# Generated by OpenFakeRAM
VERSION 5.7 ;
BUSBITCHARS "[]" ;
PROPERTYDEFINITIONS
  MACRO width INTEGER ;
  MACRO depth INTEGER ;
  MACRO banks INTEGER ;
END PROPERTYDEFINITIONS
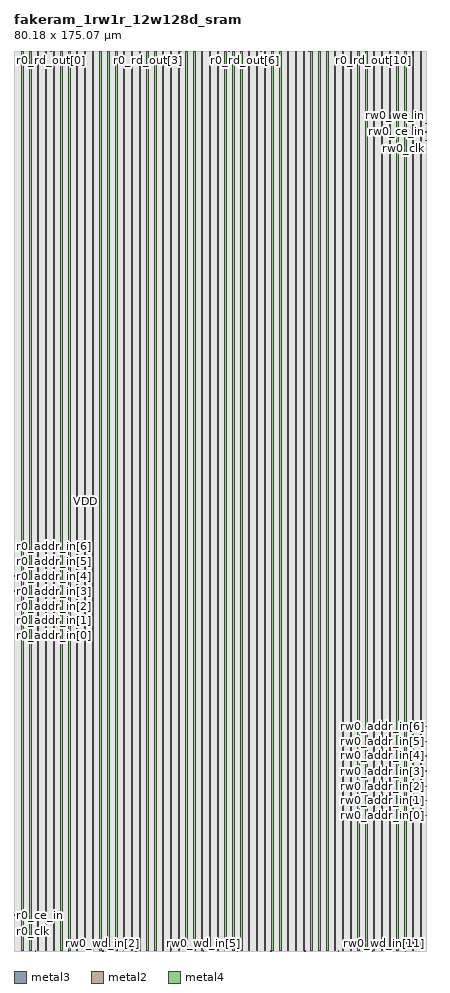
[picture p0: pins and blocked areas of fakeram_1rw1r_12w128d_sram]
MACRO fakeram_1rw1r_12w128d_sram
  PROPERTY width 12 ;
  PROPERTY depth 128 ;
  PROPERTY banks 1 ;
  FOREIGN fakeram_1rw1r_12w128d_sram 0 0 ;
  SYMMETRY X Y R90 ;
  SIZE 80.180 BY 175.070 ;
  CLASS BLOCK ;
  PIN r0_clk
    DIRECTION INPUT ;
    USE SIGNAL ;
    SHAPE ABUTMENT ;
    PORT
      LAYER metal3 ;
      RECT 0.000 5.285 0.070 5.355 ;
    END
  END r0_clk
  PIN r0_ce_in
    DIRECTION INPUT ;
    USE SIGNAL ;
    SHAPE ABUTMENT ;
    PORT
      LAYER metal3 ;
      RECT 0.000 6.965 0.070 7.035 ;
    END
  END r0_ce_in
  PIN r0_addr_in[0]
    DIRECTION INPUT ;
    USE SIGNAL ;
    SHAPE ABUTMENT ;
    PORT
      LAYER metal3 ;
      RECT 0.000 61.285 0.070 61.355 ;
    END
  END r0_addr_in[0]
  PIN r0_addr_in[1]
    DIRECTION INPUT ;
    USE SIGNAL ;
    SHAPE ABUTMENT ;
    PORT
      LAYER metal3 ;
      RECT 0.000 64.225 0.070 64.295 ;
    END
  END r0_addr_in[1]
  PIN r0_addr_in[2]
    DIRECTION INPUT ;
    USE SIGNAL ;
    SHAPE ABUTMENT ;
    PORT
      LAYER metal3 ;
      RECT 0.000 67.025 0.070 67.095 ;
    END
  END r0_addr_in[2]
  PIN r0_addr_in[3]
    DIRECTION INPUT ;
    USE SIGNAL ;
    SHAPE ABUTMENT ;
    PORT
      LAYER metal3 ;
      RECT 0.000 69.965 0.070 70.035 ;
    END
  END r0_addr_in[3]
  PIN r0_addr_in[4]
    DIRECTION INPUT ;
    USE SIGNAL ;
    SHAPE ABUTMENT ;
    PORT
      LAYER metal3 ;
      RECT 0.000 72.905 0.070 72.975 ;
    END
  END r0_addr_in[4]
  PIN r0_addr_in[5]
    DIRECTION INPUT ;
    USE SIGNAL ;
    SHAPE ABUTMENT ;
    PORT
      LAYER metal3 ;
      RECT 0.000 75.705 0.070 75.775 ;
    END
  END r0_addr_in[5]
  PIN r0_addr_in[6]
    DIRECTION INPUT ;
    USE SIGNAL ;
    SHAPE ABUTMENT ;
    PORT
      LAYER metal3 ;
      RECT 0.000 78.645 0.070 78.715 ;
    END
  END r0_addr_in[6]
  PIN rw0_rd_out[0]
    DIRECTION OUTPUT ;
    USE SIGNAL ;
    SHAPE ABUTMENT ;
    PORT
      LAYER metal2 ;
      RECT 4.145 175.000 4.215 175.070 ;
    END
  END rw0_rd_out[0]
  PIN r0_rd_out[0]
    DIRECTION OUTPUT ;
    USE SIGNAL ;
    SHAPE ABUTMENT ;
    PORT
      LAYER metal2 ;
      RECT 7.185 175.000 7.255 175.070 ;
    END
  END r0_rd_out[0]
  PIN rw0_rd_out[1]
    DIRECTION OUTPUT ;
    USE SIGNAL ;
    SHAPE ABUTMENT ;
    PORT
      LAYER metal2 ;
      RECT 10.415 175.000 10.485 175.070 ;
    END
  END rw0_rd_out[1]
  PIN r0_rd_out[1]
    DIRECTION OUTPUT ;
    USE SIGNAL ;
    SHAPE ABUTMENT ;
    PORT
      LAYER metal2 ;
      RECT 13.455 175.000 13.525 175.070 ;
    END
  END r0_rd_out[1]
  PIN rw0_rd_out[2]
    DIRECTION OUTPUT ;
    USE SIGNAL ;
    SHAPE ABUTMENT ;
    PORT
      LAYER metal2 ;
      RECT 16.685 175.000 16.755 175.070 ;
    END
  END rw0_rd_out[2]
  PIN r0_rd_out[2]
    DIRECTION OUTPUT ;
    USE SIGNAL ;
    SHAPE ABUTMENT ;
    PORT
      LAYER metal2 ;
      RECT 19.725 175.000 19.795 175.070 ;
    END
  END r0_rd_out[2]
  PIN rw0_rd_out[3]
    DIRECTION OUTPUT ;
    USE SIGNAL ;
    SHAPE ABUTMENT ;
    PORT
      LAYER metal2 ;
      RECT 22.955 175.000 23.025 175.070 ;
    END
  END rw0_rd_out[3]
  PIN r0_rd_out[3]
    DIRECTION OUTPUT ;
    USE SIGNAL ;
    SHAPE ABUTMENT ;
    PORT
      LAYER metal2 ;
      RECT 25.995 175.000 26.065 175.070 ;
    END
  END r0_rd_out[3]
  PIN rw0_rd_out[4]
    DIRECTION OUTPUT ;
    USE SIGNAL ;
    SHAPE ABUTMENT ;
    PORT
      LAYER metal2 ;
      RECT 29.225 175.000 29.295 175.070 ;
    END
  END rw0_rd_out[4]
  PIN r0_rd_out[4]
    DIRECTION OUTPUT ;
    USE SIGNAL ;
    SHAPE ABUTMENT ;
    PORT
      LAYER metal2 ;
      RECT 32.265 175.000 32.335 175.070 ;
    END
  END r0_rd_out[4]
  PIN rw0_rd_out[5]
    DIRECTION OUTPUT ;
    USE SIGNAL ;
    SHAPE ABUTMENT ;
    PORT
      LAYER metal2 ;
      RECT 35.495 175.000 35.565 175.070 ;
    END
  END rw0_rd_out[5]
  PIN r0_rd_out[5]
    DIRECTION OUTPUT ;
    USE SIGNAL ;
    SHAPE ABUTMENT ;
    PORT
      LAYER metal2 ;
      RECT 38.535 175.000 38.605 175.070 ;
    END
  END r0_rd_out[5]
  PIN rw0_rd_out[6]
    DIRECTION OUTPUT ;
    USE SIGNAL ;
    SHAPE ABUTMENT ;
    PORT
      LAYER metal2 ;
      RECT 41.765 175.000 41.835 175.070 ;
    END
  END rw0_rd_out[6]
  PIN r0_rd_out[6]
    DIRECTION OUTPUT ;
    USE SIGNAL ;
    SHAPE ABUTMENT ;
    PORT
      LAYER metal2 ;
      RECT 44.805 175.000 44.875 175.070 ;
    END
  END r0_rd_out[6]
  PIN rw0_rd_out[7]
    DIRECTION OUTPUT ;
    USE SIGNAL ;
    SHAPE ABUTMENT ;
    PORT
      LAYER metal2 ;
      RECT 48.035 175.000 48.105 175.070 ;
    END
  END rw0_rd_out[7]
  PIN r0_rd_out[7]
    DIRECTION OUTPUT ;
    USE SIGNAL ;
    SHAPE ABUTMENT ;
    PORT
      LAYER metal2 ;
      RECT 51.075 175.000 51.145 175.070 ;
    END
  END r0_rd_out[7]
  PIN rw0_rd_out[8]
    DIRECTION OUTPUT ;
    USE SIGNAL ;
    SHAPE ABUTMENT ;
    PORT
      LAYER metal2 ;
      RECT 54.305 175.000 54.375 175.070 ;
    END
  END rw0_rd_out[8]
  PIN r0_rd_out[8]
    DIRECTION OUTPUT ;
    USE SIGNAL ;
    SHAPE ABUTMENT ;
    PORT
      LAYER metal2 ;
      RECT 57.345 175.000 57.415 175.070 ;
    END
  END r0_rd_out[8]
  PIN rw0_rd_out[9]
    DIRECTION OUTPUT ;
    USE SIGNAL ;
    SHAPE ABUTMENT ;
    PORT
      LAYER metal2 ;
      RECT 60.575 175.000 60.645 175.070 ;
    END
  END rw0_rd_out[9]
  PIN r0_rd_out[9]
    DIRECTION OUTPUT ;
    USE SIGNAL ;
    SHAPE ABUTMENT ;
    PORT
      LAYER metal2 ;
      RECT 63.615 175.000 63.685 175.070 ;
    END
  END r0_rd_out[9]
  PIN rw0_rd_out[10]
    DIRECTION OUTPUT ;
    USE SIGNAL ;
    SHAPE ABUTMENT ;
    PORT
      LAYER metal2 ;
      RECT 66.845 175.000 66.915 175.070 ;
    END
  END rw0_rd_out[10]
  PIN r0_rd_out[10]
    DIRECTION OUTPUT ;
    USE SIGNAL ;
    SHAPE ABUTMENT ;
    PORT
      LAYER metal2 ;
      RECT 69.885 175.000 69.955 175.070 ;
    END
  END r0_rd_out[10]
  PIN rw0_rd_out[11]
    DIRECTION OUTPUT ;
    USE SIGNAL ;
    SHAPE ABUTMENT ;
    PORT
      LAYER metal2 ;
      RECT 73.115 175.000 73.185 175.070 ;
    END
  END rw0_rd_out[11]
  PIN r0_rd_out[11]
    DIRECTION OUTPUT ;
    USE SIGNAL ;
    SHAPE ABUTMENT ;
    PORT
      LAYER metal2 ;
      RECT 76.155 175.000 76.225 175.070 ;
    END
  END r0_rd_out[11]
  PIN rw0_clk
    DIRECTION INPUT ;
    USE SIGNAL ;
    SHAPE ABUTMENT ;
    PORT
      LAYER metal3 ;
      RECT 80.110 157.605 80.180 157.675 ;
    END
  END rw0_clk
  PIN rw0_ce_in
    DIRECTION INPUT ;
    USE SIGNAL ;
    SHAPE ABUTMENT ;
    PORT
      LAYER metal3 ;
      RECT 80.110 159.285 80.180 159.355 ;
    END
  END rw0_ce_in
  PIN rw0_we_in
    DIRECTION INPUT ;
    USE SIGNAL ;
    SHAPE ABUTMENT ;
    PORT
      LAYER metal3 ;
      RECT 80.110 160.965 80.180 161.035 ;
    END
  END rw0_we_in
  PIN rw0_addr_in[0]
    DIRECTION INPUT ;
    USE SIGNAL ;
    SHAPE ABUTMENT ;
    PORT
      LAYER metal3 ;
      RECT 80.110 26.285 80.180 26.355 ;
    END
  END rw0_addr_in[0]
  PIN rw0_addr_in[1]
    DIRECTION INPUT ;
    USE SIGNAL ;
    SHAPE ABUTMENT ;
    PORT
      LAYER metal3 ;
      RECT 80.110 29.225 80.180 29.295 ;
    END
  END rw0_addr_in[1]
  PIN rw0_addr_in[2]
    DIRECTION INPUT ;
    USE SIGNAL ;
    SHAPE ABUTMENT ;
    PORT
      LAYER metal3 ;
      RECT 80.110 32.025 80.180 32.095 ;
    END
  END rw0_addr_in[2]
  PIN rw0_addr_in[3]
    DIRECTION INPUT ;
    USE SIGNAL ;
    SHAPE ABUTMENT ;
    PORT
      LAYER metal3 ;
      RECT 80.110 34.965 80.180 35.035 ;
    END
  END rw0_addr_in[3]
  PIN rw0_addr_in[4]
    DIRECTION INPUT ;
    USE SIGNAL ;
    SHAPE ABUTMENT ;
    PORT
      LAYER metal3 ;
      RECT 80.110 37.905 80.180 37.975 ;
    END
  END rw0_addr_in[4]
  PIN rw0_addr_in[5]
    DIRECTION INPUT ;
    USE SIGNAL ;
    SHAPE ABUTMENT ;
    PORT
      LAYER metal3 ;
      RECT 80.110 40.705 80.180 40.775 ;
    END
  END rw0_addr_in[5]
  PIN rw0_addr_in[6]
    DIRECTION INPUT ;
    USE SIGNAL ;
    SHAPE ABUTMENT ;
    PORT
      LAYER metal3 ;
      RECT 80.110 43.645 80.180 43.715 ;
    END
  END rw0_addr_in[6]
  PIN rw0_wd_in[0]
    DIRECTION INPUT ;
    USE SIGNAL ;
    SHAPE ABUTMENT ;
    PORT
      LAYER metal2 ;
      RECT 4.145 0.000 4.215 0.070 ;
    END
  END rw0_wd_in[0]
  PIN rw0_wd_in[1]
    DIRECTION INPUT ;
    USE SIGNAL ;
    SHAPE ABUTMENT ;
    PORT
      LAYER metal2 ;
      RECT 10.605 0.000 10.675 0.070 ;
    END
  END rw0_wd_in[1]
  PIN rw0_wd_in[2]
    DIRECTION INPUT ;
    USE SIGNAL ;
    SHAPE ABUTMENT ;
    PORT
      LAYER metal2 ;
      RECT 17.255 0.000 17.325 0.070 ;
    END
  END rw0_wd_in[2]
  PIN rw0_wd_in[3]
    DIRECTION INPUT ;
    USE SIGNAL ;
    SHAPE ABUTMENT ;
    PORT
      LAYER metal2 ;
      RECT 23.715 0.000 23.785 0.070 ;
    END
  END rw0_wd_in[3]
  PIN rw0_wd_in[4]
    DIRECTION INPUT ;
    USE SIGNAL ;
    SHAPE ABUTMENT ;
    PORT
      LAYER metal2 ;
      RECT 30.365 0.000 30.435 0.070 ;
    END
  END rw0_wd_in[4]
  PIN rw0_wd_in[5]
    DIRECTION INPUT ;
    USE SIGNAL ;
    SHAPE ABUTMENT ;
    PORT
      LAYER metal2 ;
      RECT 36.825 0.000 36.895 0.070 ;
    END
  END rw0_wd_in[5]
  PIN rw0_wd_in[6]
    DIRECTION INPUT ;
    USE SIGNAL ;
    SHAPE ABUTMENT ;
    PORT
      LAYER metal2 ;
      RECT 43.475 0.000 43.545 0.070 ;
    END
  END rw0_wd_in[6]
  PIN rw0_wd_in[7]
    DIRECTION INPUT ;
    USE SIGNAL ;
    SHAPE ABUTMENT ;
    PORT
      LAYER metal2 ;
      RECT 49.935 0.000 50.005 0.070 ;
    END
  END rw0_wd_in[7]
  PIN rw0_wd_in[8]
    DIRECTION INPUT ;
    USE SIGNAL ;
    SHAPE ABUTMENT ;
    PORT
      LAYER metal2 ;
      RECT 56.585 0.000 56.655 0.070 ;
    END
  END rw0_wd_in[8]
  PIN rw0_wd_in[9]
    DIRECTION INPUT ;
    USE SIGNAL ;
    SHAPE ABUTMENT ;
    PORT
      LAYER metal2 ;
      RECT 63.045 0.000 63.115 0.070 ;
    END
  END rw0_wd_in[9]
  PIN rw0_wd_in[10]
    DIRECTION INPUT ;
    USE SIGNAL ;
    SHAPE ABUTMENT ;
    PORT
      LAYER metal2 ;
      RECT 69.695 0.000 69.765 0.070 ;
    END
  END rw0_wd_in[10]
  PIN rw0_wd_in[11]
    DIRECTION INPUT ;
    USE SIGNAL ;
    SHAPE ABUTMENT ;
    PORT
      LAYER metal2 ;
      RECT 76.155 0.000 76.225 0.070 ;
    END
  END rw0_wd_in[11]
  PIN VSS
    DIRECTION INOUT ;
    USE GROUND ;
    PORT
      LAYER metal4 ;
      RECT 3.040 0.140 3.320 174.930 ;
      RECT 6.080 0.140 6.360 174.930 ;
      RECT 9.120 0.140 9.400 174.930 ;
      RECT 12.160 0.140 12.440 174.930 ;
      RECT 15.200 0.140 15.480 174.930 ;
      RECT 18.240 0.140 18.520 174.930 ;
      RECT 21.280 0.140 21.560 174.930 ;
      RECT 24.320 0.140 24.600 174.930 ;
      RECT 27.360 0.140 27.640 174.930 ;
      RECT 30.400 0.140 30.680 174.930 ;
      RECT 33.440 0.140 33.720 174.930 ;
      RECT 36.480 0.140 36.760 174.930 ;
      RECT 39.520 0.140 39.800 174.930 ;
      RECT 42.560 0.140 42.840 174.930 ;
      RECT 45.600 0.140 45.880 174.930 ;
      RECT 48.640 0.140 48.920 174.930 ;
      RECT 51.680 0.140 51.960 174.930 ;
      RECT 54.720 0.140 55.000 174.930 ;
      RECT 57.760 0.140 58.040 174.930 ;
      RECT 60.800 0.140 61.080 174.930 ;
      RECT 63.840 0.140 64.120 174.930 ;
      RECT 66.880 0.140 67.160 174.930 ;
      RECT 69.920 0.140 70.200 174.930 ;
      RECT 72.960 0.140 73.240 174.930 ;
      RECT 76.000 0.140 76.280 174.930 ;
      RECT 79.040 0.140 79.320 174.930 ;
    END
  END VSS
  PIN VDD
    DIRECTION INOUT ;
    USE POWER ;
    PORT
      LAYER metal4 ;
      RECT 1.520 0.140 1.800 174.930 ;
      RECT 4.560 0.140 4.840 174.930 ;
      RECT 7.600 0.140 7.880 174.930 ;
      RECT 10.640 0.140 10.920 174.930 ;
      RECT 13.680 0.140 13.960 174.930 ;
      RECT 16.720 0.140 17.000 174.930 ;
      RECT 19.760 0.140 20.040 174.930 ;
      RECT 22.800 0.140 23.080 174.930 ;
      RECT 25.840 0.140 26.120 174.930 ;
      RECT 28.880 0.140 29.160 174.930 ;
      RECT 31.920 0.140 32.200 174.930 ;
      RECT 34.960 0.140 35.240 174.930 ;
      RECT 38.000 0.140 38.280 174.930 ;
      RECT 41.040 0.140 41.320 174.930 ;
      RECT 44.080 0.140 44.360 174.930 ;
      RECT 47.120 0.140 47.400 174.930 ;
      RECT 50.160 0.140 50.440 174.930 ;
      RECT 53.200 0.140 53.480 174.930 ;
      RECT 56.240 0.140 56.520 174.930 ;
      RECT 59.280 0.140 59.560 174.930 ;
      RECT 62.320 0.140 62.600 174.930 ;
      RECT 65.360 0.140 65.640 174.930 ;
      RECT 68.400 0.140 68.680 174.930 ;
      RECT 71.440 0.140 71.720 174.930 ;
      RECT 74.480 0.140 74.760 174.930 ;
      RECT 77.520 0.140 77.800 174.930 ;
    END
  END VDD
  OBS
    LAYER metal1 ;
    RECT 0 0 80.180 175.070 ;
    LAYER metal2 ;
    RECT 0 0 80.180 175.070 ;
    LAYER metal3 ;
    RECT 0 0 80.180 175.070 ;
    LAYER metal4 ;
    RECT 0 0 80.180 175.070 ;
    LAYER OVERLAP ;
    RECT 0 0 80.180 175.070 ;
  END
END fakeram_1rw1r_12w128d_sram

END LIBRARY
